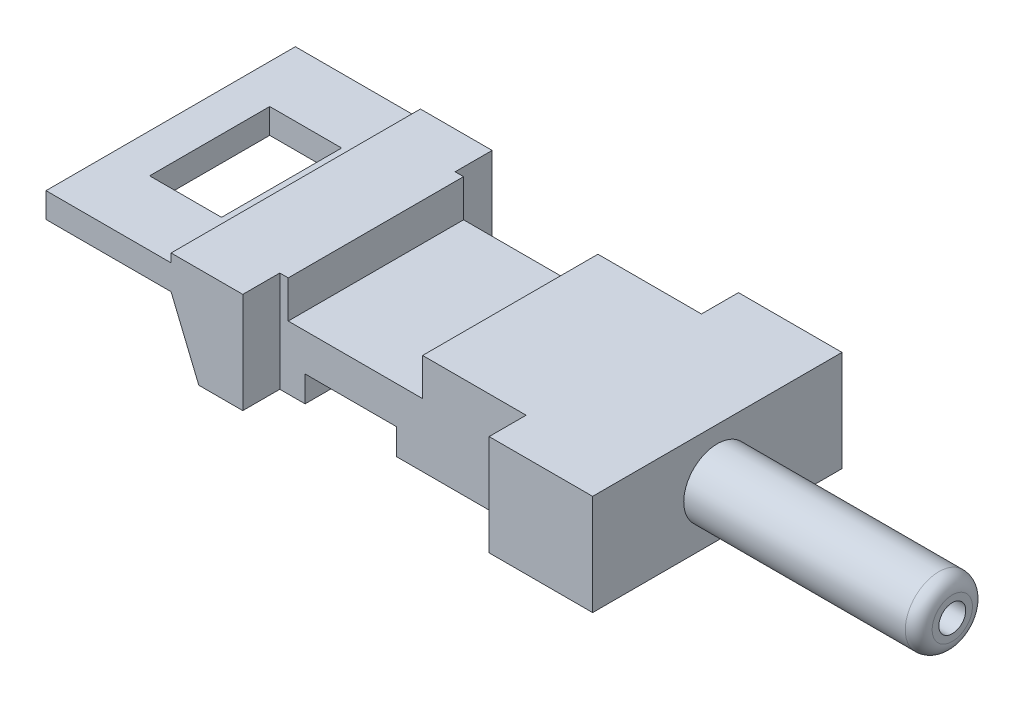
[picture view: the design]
ISO-10303-21;
HEADER;
FILE_DESCRIPTION(('STEP AP214'),'2;1');
FILE_NAME('part.step','',(''),(''),'','','');
FILE_SCHEMA(('AUTOMOTIVE_DESIGN { 1 0 10303 214 1 1 1 1 }'));
ENDSEC;
DATA;
#1=APPLICATION_CONTEXT('core data for automotive mechanical design processes');
#2=APPLICATION_PROTOCOL_DEFINITION('international standard','automotive_design',2000,#1);
#3=PRODUCT_CONTEXT('',#1,'mechanical');
#4=PRODUCT('Part','Part','',(#3));
#5=PRODUCT_RELATED_PRODUCT_CATEGORY('part','',(#4));
#6=PRODUCT_DEFINITION_FORMATION('','',#4);
#7=PRODUCT_DEFINITION_CONTEXT('part definition',#1,'design');
#8=PRODUCT_DEFINITION('design','',#6,#7);
#9=PRODUCT_DEFINITION_SHAPE('','',#8);
#10=(LENGTH_UNIT() NAMED_UNIT(*) SI_UNIT(.MILLI.,.METRE.));
#11=(NAMED_UNIT(*) PLANE_ANGLE_UNIT() SI_UNIT($,.RADIAN.));
#12=(NAMED_UNIT(*) SI_UNIT($,.STERADIAN.) SOLID_ANGLE_UNIT());
#13=UNCERTAINTY_MEASURE_WITH_UNIT(LENGTH_MEASURE(1.E-05),#10,'distance_accuracy_value','');
#14=(GEOMETRIC_REPRESENTATION_CONTEXT(3) GLOBAL_UNCERTAINTY_ASSIGNED_CONTEXT((#13)) GLOBAL_UNIT_ASSIGNED_CONTEXT((#10,
#11,#12)) REPRESENTATION_CONTEXT('',''));
#15=CARTESIAN_POINT('',(0.,0.,0.));
#16=DIRECTION('',(0.,0.,1.));
#17=DIRECTION('',(1.,0.,0.));
#18=AXIS2_PLACEMENT_3D('',#15,#16,#17);
#19=CARTESIAN_POINT('',(-40.7086650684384,5.,18.5695273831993));
#20=DIRECTION('',(0.,0.,-1.));
#21=DIRECTION('',(-1.,0.,0.));
#22=AXIS2_PLACEMENT_3D('',#19,#20,#21);
#23=PLANE('',#22);
#24=DIRECTION('',(1.,0.,0.));
#25=VECTOR('',#24,1.);
#26=CARTESIAN_POINT('',(-40.7086650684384,3.7238100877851,18.5695273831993));
#27=LINE('',#26,#25);
#28=CARTESIAN_POINT('',(-40.7086650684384,3.7238100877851,18.5695273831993));
#29=VERTEX_POINT('',#28);
#30=CARTESIAN_POINT('',(-22.0774506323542,3.7238100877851,18.5695273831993));
#31=VERTEX_POINT('',#30);
#32=EDGE_CURVE('E245',#29,#31,#27,.T.);
#33=ORIENTED_EDGE('',*,*,#32,.F.);
#34=DIRECTION('',(0.,-1.,0.));
#35=VECTOR('',#34,1.);
#36=CARTESIAN_POINT('',(-40.7086650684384,5.,18.5695273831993));
#37=LINE('',#36,#35);
#38=CARTESIAN_POINT('',(-40.7086650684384,0.,18.5695273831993));
#39=VERTEX_POINT('',#38);
#40=EDGE_CURVE('E255',#29,#39,#37,.T.);
#41=ORIENTED_EDGE('',*,*,#40,.T.);
#42=DIRECTION('',(-1.,0.,0.));
#43=VECTOR('',#42,1.);
#44=CARTESIAN_POINT('',(-40.7086650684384,0.,18.5695273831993));
#45=LINE('',#44,#43);
#46=CARTESIAN_POINT('',(-22.0774506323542,0.,18.5695273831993));
#47=VERTEX_POINT('',#46);
#48=EDGE_CURVE('E464',#47,#39,#45,.T.);
#49=ORIENTED_EDGE('',*,*,#48,.F.);
#50=DIRECTION('',(-0.381591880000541,0.924330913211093,0.));
#51=VECTOR('',#50,1.);
#52=CARTESIAN_POINT('',(-22.0774506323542,0.,18.5695273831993));
#53=LINE('',#52,#51);
#54=CARTESIAN_POINT('',(-17.9491468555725,-10.,18.5695273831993));
#55=VERTEX_POINT('',#54);
#56=EDGE_CURVE('E456',#55,#47,#53,.T.);
#57=ORIENTED_EDGE('',*,*,#56,.F.);
#58=DIRECTION('',(1.,0.,0.));
#59=VECTOR('',#58,1.);
#60=CARTESIAN_POINT('',(-40.7086650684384,-10.,18.5695273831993));
#61=LINE('',#60,#59);
#62=CARTESIAN_POINT('',(-11.3977082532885,-10.,18.5695273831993));
#63=VERTEX_POINT('',#62);
#64=EDGE_CURVE('E478',#55,#63,#61,.T.);
#65=ORIENTED_EDGE('',*,*,#64,.T.);
#66=DIRECTION('',(0.,1.,0.));
#67=VECTOR('',#66,1.);
#68=CARTESIAN_POINT('',(-11.3977082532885,-10.001,18.5695273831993));
#69=LINE('',#68,#67);
#70=CARTESIAN_POINT('',(-11.3977082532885,5.,18.5695273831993));
#71=VERTEX_POINT('',#70);
#72=EDGE_CURVE('E400',#63,#71,#69,.T.);
#73=ORIENTED_EDGE('',*,*,#72,.T.);
#74=DIRECTION('',(1.,0.,0.));
#75=VECTOR('',#74,1.);
#76=CARTESIAN_POINT('',(-40.7086650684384,5.,18.5695273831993));
#77=LINE('',#76,#75);
#78=CARTESIAN_POINT('',(-22.0774506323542,5.,18.5695273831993));
#79=VERTEX_POINT('',#78);
#80=EDGE_CURVE('E489',#79,#71,#77,.T.);
#81=ORIENTED_EDGE('',*,*,#80,.F.);
#82=DIRECTION('',(0.,1.,0.));
#83=VECTOR('',#82,1.);
#84=CARTESIAN_POINT('',(-22.0774506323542,3.7238100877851,18.5695273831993));
#85=LINE('',#84,#83);
#86=EDGE_CURVE('E46',#31,#79,#85,.T.);
#87=ORIENTED_EDGE('',*,*,#86,.F.);
#88=EDGE_LOOP('',(#33,#41,#49,#57,#65,#73,#81,#87));
#89=FACE_BOUND('',#88,.T.);
#90=ADVANCED_FACE('F31',(#89),#23,.F.);
#91=CARTESIAN_POINT('',(-40.7086650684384,5.,-18.5695273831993));
#92=DIRECTION('',(1.,0.,0.));
#93=DIRECTION('',(0.,0.,-1.));
#94=AXIS2_PLACEMENT_3D('',#91,#92,#93);
#95=PLANE('',#94);
#96=DIRECTION('',(0.,0.,-1.));
#97=VECTOR('',#96,1.);
#98=CARTESIAN_POINT('',(-40.7086650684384,3.7238100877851,18.5695273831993));
#99=LINE('',#98,#97);
#100=CARTESIAN_POINT('',(-40.7086650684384,3.7238100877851,-18.5695273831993));
#101=VERTEX_POINT('',#100);
#102=EDGE_CURVE('E241',#29,#101,#99,.T.);
#103=ORIENTED_EDGE('',*,*,#102,.T.);
#104=DIRECTION('',(0.,-1.,0.));
#105=VECTOR('',#104,1.);
#106=CARTESIAN_POINT('',(-40.7086650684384,5.,-18.5695273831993));
#107=LINE('',#106,#105);
#108=CARTESIAN_POINT('',(-40.7086650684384,0.,-18.5695273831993));
#109=VERTEX_POINT('',#108);
#110=EDGE_CURVE('E497',#101,#109,#107,.T.);
#111=ORIENTED_EDGE('',*,*,#110,.T.);
#112=DIRECTION('',(0.,0.,1.));
#113=VECTOR('',#112,1.);
#114=CARTESIAN_POINT('',(-40.7086650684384,0.,-18.5695273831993));
#115=LINE('',#114,#113);
#116=EDGE_CURVE('E262',#109,#39,#115,.T.);
#117=ORIENTED_EDGE('',*,*,#116,.T.);
#118=ORIENTED_EDGE('',*,*,#40,.F.);
#119=EDGE_LOOP('',(#103,#111,#117,#118));
#120=FACE_BOUND('',#119,.T.);
#121=ADVANCED_FACE('F33',(#120),#95,.F.);
#122=CARTESIAN_POINT('',(-40.7086650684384,5.,-18.5695273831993));
#123=DIRECTION('',(0.,0.,1.));
#124=DIRECTION('',(1.,0.,0.));
#125=AXIS2_PLACEMENT_3D('',#122,#123,#124);
#126=PLANE('',#125);
#127=DIRECTION('',(-1.,0.,0.));
#128=VECTOR('',#127,1.);
#129=CARTESIAN_POINT('',(-40.7086650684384,3.7238100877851,-18.5695273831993));
#130=LINE('',#129,#128);
#131=CARTESIAN_POINT('',(-22.0774506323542,3.7238100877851,-18.5695273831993));
#132=VERTEX_POINT('',#131);
#133=EDGE_CURVE('E247',#132,#101,#130,.T.);
#134=ORIENTED_EDGE('',*,*,#133,.F.);
#135=DIRECTION('',(0.,-1.,0.));
#136=VECTOR('',#135,1.);
#137=CARTESIAN_POINT('',(-22.0774506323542,5.00000000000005,-18.5695273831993));
#138=LINE('',#137,#136);
#139=CARTESIAN_POINT('',(-22.0774506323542,5.,-18.5695273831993));
#140=VERTEX_POINT('',#139);
#141=EDGE_CURVE('E299',#140,#132,#138,.T.);
#142=ORIENTED_EDGE('',*,*,#141,.F.);
#143=DIRECTION('',(-1.,0.,0.));
#144=VECTOR('',#143,1.);
#145=CARTESIAN_POINT('',(-40.7086650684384,5.,-18.5695273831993));
#146=LINE('',#145,#144);
#147=CARTESIAN_POINT('',(-11.3977082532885,5.,-18.5695273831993));
#148=VERTEX_POINT('',#147);
#149=EDGE_CURVE('E493',#148,#140,#146,.T.);
#150=ORIENTED_EDGE('',*,*,#149,.F.);
#151=DIRECTION('',(0.,1.,0.));
#152=VECTOR('',#151,1.);
#153=CARTESIAN_POINT('',(-11.3977082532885,-10.001,-18.5695273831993));
#154=LINE('',#153,#152);
#155=CARTESIAN_POINT('',(-11.3977082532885,-10.,-18.5695273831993));
#156=VERTEX_POINT('',#155);
#157=EDGE_CURVE('E356',#156,#148,#154,.T.);
#158=ORIENTED_EDGE('',*,*,#157,.F.);
#159=DIRECTION('',(-1.,0.,0.));
#160=VECTOR('',#159,1.);
#161=CARTESIAN_POINT('',(-40.7086650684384,-10.,-18.5695273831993));
#162=LINE('',#161,#160);
#163=CARTESIAN_POINT('',(-17.9491468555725,-10.,-18.5695273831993));
#164=VERTEX_POINT('',#163);
#165=EDGE_CURVE('E484',#156,#164,#162,.T.);
#166=ORIENTED_EDGE('',*,*,#165,.T.);
#167=DIRECTION('',(-0.381591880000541,0.924330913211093,0.));
#168=VECTOR('',#167,1.);
#169=CARTESIAN_POINT('',(-22.0774506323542,0.,-18.5695273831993));
#170=LINE('',#169,#168);
#171=CARTESIAN_POINT('',(-22.0774506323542,0.,-18.5695273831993));
#172=VERTEX_POINT('',#171);
#173=EDGE_CURVE('E466',#164,#172,#170,.T.);
#174=ORIENTED_EDGE('',*,*,#173,.T.);
#175=DIRECTION('',(-1.,0.,0.));
#176=VECTOR('',#175,1.);
#177=CARTESIAN_POINT('',(-40.7086650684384,0.,-18.5695273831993));
#178=LINE('',#177,#176);
#179=EDGE_CURVE('E469',#172,#109,#178,.T.);
#180=ORIENTED_EDGE('',*,*,#179,.T.);
#181=ORIENTED_EDGE('',*,*,#110,.F.);
#182=EDGE_LOOP('',(#134,#142,#150,#158,#166,#174,#180,#181));
#183=FACE_BOUND('',#182,.T.);
#184=ADVANCED_FACE('F603',(#183),#126,.F.);
#185=CARTESIAN_POINT('',(-40.7086650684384,5.,18.5695273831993));
#186=DIRECTION('',(0.,1.,0.));
#187=DIRECTION('',(0.,0.,1.));
#188=AXIS2_PLACEMENT_3D('',#185,#186,#187);
#189=PLANE('',#188);
#190=ORIENTED_EDGE('',*,*,#149,.T.);
#191=DIRECTION('',(0.,0.,-1.));
#192=VECTOR('',#191,1.);
#193=CARTESIAN_POINT('',(-22.0774506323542,5.,18.5695273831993));
#194=LINE('',#193,#192);
#195=EDGE_CURVE('E251',#79,#140,#194,.T.);
#196=ORIENTED_EDGE('',*,*,#195,.F.);
#197=ORIENTED_EDGE('',*,*,#80,.T.);
#198=DIRECTION('',(0.,0.,1.));
#199=VECTOR('',#198,1.);
#200=CARTESIAN_POINT('',(-11.3977082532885,5.,13.058004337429));
#201=LINE('',#200,#199);
#202=CARTESIAN_POINT('',(-11.3977082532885,5.,13.058004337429));
#203=VERTEX_POINT('',#202);
#204=EDGE_CURVE('E396',#203,#71,#201,.T.);
#205=ORIENTED_EDGE('',*,*,#204,.F.);
#206=DIRECTION('',(-1.,0.,0.));
#207=VECTOR('',#206,1.);
#208=CARTESIAN_POINT('',(25.2903479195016,5.,13.058004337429));
#209=LINE('',#208,#207);
#210=CARTESIAN_POINT('',(-10.1412679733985,5.,13.058004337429));
#211=VERTEX_POINT('',#210);
#212=EDGE_CURVE('E392',#211,#203,#209,.T.);
#213=ORIENTED_EDGE('',*,*,#212,.F.);
#214=DIRECTION('',(0.,0.,1.));
#215=VECTOR('',#214,1.);
#216=CARTESIAN_POINT('',(-10.1412679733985,5.,-18.5695273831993));
#217=LINE('',#216,#215);
#218=CARTESIAN_POINT('',(-10.1412679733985,5.,-13.058004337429));
#219=VERTEX_POINT('',#218);
#220=EDGE_CURVE('E448',#219,#211,#217,.T.);
#221=ORIENTED_EDGE('',*,*,#220,.F.);
#222=DIRECTION('',(1.,0.,0.));
#223=VECTOR('',#222,1.);
#224=CARTESIAN_POINT('',(25.2903479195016,5.,-13.0580043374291));
#225=LINE('',#224,#223);
#226=CARTESIAN_POINT('',(-11.3977082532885,5.,-13.058004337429));
#227=VERTEX_POINT('',#226);
#228=EDGE_CURVE('E352',#227,#219,#225,.T.);
#229=ORIENTED_EDGE('',*,*,#228,.F.);
#230=DIRECTION('',(0.,0.,1.));
#231=VECTOR('',#230,1.);
#232=CARTESIAN_POINT('',(-11.3977082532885,5.,-13.058004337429));
#233=LINE('',#232,#231);
#234=EDGE_CURVE('E348',#148,#227,#233,.T.);
#235=ORIENTED_EDGE('',*,*,#234,.F.);
#236=EDGE_LOOP('',(#190,#196,#197,#205,#213,#221,#229,#235));
#237=FACE_BOUND('',#236,.T.);
#238=ADVANCED_FACE('F570',(#237),#189,.T.);
#239=CARTESIAN_POINT('',(-34.9005323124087,-10.001,-8.94289846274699));
#240=DIRECTION('',(-1.,0.,0.));
#241=DIRECTION('',(0.,0.,1.));
#242=AXIS2_PLACEMENT_3D('',#239,#240,#241);
#243=PLANE('',#242);
#244=DIRECTION('',(0.,0.,-1.));
#245=VECTOR('',#244,1.);
#246=CARTESIAN_POINT('',(-34.9005323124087,3.7238100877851,-8.94289846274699));
#247=LINE('',#246,#245);
#248=CARTESIAN_POINT('',(-34.9005323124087,3.7238100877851,8.94289846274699));
#249=VERTEX_POINT('',#248);
#250=CARTESIAN_POINT('',(-34.9005323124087,3.7238100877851,-8.94289846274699));
#251=VERTEX_POINT('',#250);
#252=EDGE_CURVE('E925',#249,#251,#247,.T.);
#253=ORIENTED_EDGE('',*,*,#252,.F.);
#254=DIRECTION('',(0.,1.,0.));
#255=VECTOR('',#254,1.);
#256=CARTESIAN_POINT('',(-34.9005323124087,-10.001,8.94289846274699));
#257=LINE('',#256,#255);
#258=CARTESIAN_POINT('',(-34.9005323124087,0.,8.94289846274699));
#259=VERTEX_POINT('',#258);
#260=EDGE_CURVE('E433',#259,#249,#257,.T.);
#261=ORIENTED_EDGE('',*,*,#260,.F.);
#262=DIRECTION('',(0.,0.,-1.));
#263=VECTOR('',#262,1.);
#264=CARTESIAN_POINT('',(-34.9005323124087,0.,-8.94289846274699));
#265=LINE('',#264,#263);
#266=CARTESIAN_POINT('',(-34.9005323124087,0.,-8.94289846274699));
#267=VERTEX_POINT('',#266);
#268=EDGE_CURVE('E430',#259,#267,#265,.T.);
#269=ORIENTED_EDGE('',*,*,#268,.T.);
#270=DIRECTION('',(0.,1.,0.));
#271=VECTOR('',#270,1.);
#272=CARTESIAN_POINT('',(-34.9005323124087,-10.001,-8.94289846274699));
#273=LINE('',#272,#271);
#274=EDGE_CURVE('E434',#267,#251,#273,.T.);
#275=ORIENTED_EDGE('',*,*,#274,.T.);
#276=EDGE_LOOP('',(#253,#261,#269,#275));
#277=FACE_BOUND('',#276,.T.);
#278=ADVANCED_FACE('F618',(#277),#243,.F.);
#279=CARTESIAN_POINT('',(-34.9005323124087,-10.001,-8.94289846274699));
#280=DIRECTION('',(0.,0.,-1.));
#281=DIRECTION('',(-1.,0.,0.));
#282=AXIS2_PLACEMENT_3D('',#279,#280,#281);
#283=PLANE('',#282);
#284=DIRECTION('',(1.,0.,0.));
#285=VECTOR('',#284,1.);
#286=CARTESIAN_POINT('',(-34.9005323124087,3.7238100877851,-8.94289846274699));
#287=LINE('',#286,#285);
#288=CARTESIAN_POINT('',(-24.1925625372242,3.7238100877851,-8.94289846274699));
#289=VERTEX_POINT('',#288);
#290=EDGE_CURVE('E54',#251,#289,#287,.T.);
#291=ORIENTED_EDGE('',*,*,#290,.F.);
#292=ORIENTED_EDGE('',*,*,#274,.F.);
#293=DIRECTION('',(1.,0.,0.));
#294=VECTOR('',#293,1.);
#295=CARTESIAN_POINT('',(-34.9005323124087,0.,-8.94289846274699));
#296=LINE('',#295,#294);
#297=CARTESIAN_POINT('',(-24.1925625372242,0.,-8.94289846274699));
#298=VERTEX_POINT('',#297);
#299=EDGE_CURVE('E427',#267,#298,#296,.T.);
#300=ORIENTED_EDGE('',*,*,#299,.T.);
#301=DIRECTION('',(0.,1.,0.));
#302=VECTOR('',#301,1.);
#303=CARTESIAN_POINT('',(-24.1925625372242,-10.001,-8.94289846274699));
#304=LINE('',#303,#302);
#305=EDGE_CURVE('E437',#298,#289,#304,.T.);
#306=ORIENTED_EDGE('',*,*,#305,.T.);
#307=EDGE_LOOP('',(#291,#292,#300,#306));
#308=FACE_BOUND('',#307,.T.);
#309=ADVANCED_FACE('F623',(#308),#283,.F.);
#310=CARTESIAN_POINT('',(-24.1925625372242,-10.001,-8.94289846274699));
#311=DIRECTION('',(1.,0.,0.));
#312=DIRECTION('',(0.,0.,-1.));
#313=AXIS2_PLACEMENT_3D('',#310,#311,#312);
#314=PLANE('',#313);
#315=DIRECTION('',(0.,0.,1.));
#316=VECTOR('',#315,1.);
#317=CARTESIAN_POINT('',(-24.1925625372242,3.7238100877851,-8.94289846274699));
#318=LINE('',#317,#316);
#319=CARTESIAN_POINT('',(-24.1925625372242,3.7238100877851,8.94289846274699));
#320=VERTEX_POINT('',#319);
#321=EDGE_CURVE('E258',#289,#320,#318,.T.);
#322=ORIENTED_EDGE('',*,*,#321,.F.);
#323=ORIENTED_EDGE('',*,*,#305,.F.);
#324=DIRECTION('',(0.,0.,1.));
#325=VECTOR('',#324,1.);
#326=CARTESIAN_POINT('',(-24.1925625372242,0.,-8.94289846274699));
#327=LINE('',#326,#325);
#328=CARTESIAN_POINT('',(-24.1925625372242,0.,8.94289846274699));
#329=VERTEX_POINT('',#328);
#330=EDGE_CURVE('E425',#298,#329,#327,.T.);
#331=ORIENTED_EDGE('',*,*,#330,.T.);
#332=DIRECTION('',(0.,1.,0.));
#333=VECTOR('',#332,1.);
#334=CARTESIAN_POINT('',(-24.1925625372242,-10.001,8.94289846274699));
#335=LINE('',#334,#333);
#336=EDGE_CURVE('E439',#329,#320,#335,.T.);
#337=ORIENTED_EDGE('',*,*,#336,.T.);
#338=EDGE_LOOP('',(#322,#323,#331,#337));
#339=FACE_BOUND('',#338,.T.);
#340=ADVANCED_FACE('F637',(#339),#314,.F.);
#341=CARTESIAN_POINT('',(-34.9005323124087,-10.001,8.94289846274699));
#342=DIRECTION('',(0.,0.,1.));
#343=DIRECTION('',(1.,0.,0.));
#344=AXIS2_PLACEMENT_3D('',#341,#342,#343);
#345=PLANE('',#344);
#346=DIRECTION('',(-1.,0.,0.));
#347=VECTOR('',#346,1.);
#348=CARTESIAN_POINT('',(-34.9005323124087,3.7238100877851,8.94289846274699));
#349=LINE('',#348,#347);
#350=EDGE_CURVE('E11',#320,#249,#349,.T.);
#351=ORIENTED_EDGE('',*,*,#350,.F.);
#352=ORIENTED_EDGE('',*,*,#336,.F.);
#353=DIRECTION('',(-1.,0.,0.));
#354=VECTOR('',#353,1.);
#355=CARTESIAN_POINT('',(-34.9005323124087,0.,8.94289846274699));
#356=LINE('',#355,#354);
#357=EDGE_CURVE('E436',#329,#259,#356,.T.);
#358=ORIENTED_EDGE('',*,*,#357,.T.);
#359=ORIENTED_EDGE('',*,*,#260,.T.);
#360=EDGE_LOOP('',(#351,#352,#358,#359));
#361=FACE_BOUND('',#360,.T.);
#362=ADVANCED_FACE('F633',(#361),#345,.F.);
#363=CARTESIAN_POINT('',(40.7086650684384,5.,-18.5695273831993));
#364=DIRECTION('',(-1.,0.,0.));
#365=DIRECTION('',(0.,0.,1.));
#366=AXIS2_PLACEMENT_3D('',#363,#364,#365);
#367=PLANE('',#366);
#368=DIRECTION('',(0.,-1.,0.));
#369=VECTOR('',#368,1.);
#370=CARTESIAN_POINT('',(40.7086650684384,5.,18.5695273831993));
#371=LINE('',#370,#369);
#372=CARTESIAN_POINT('',(40.7086650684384,5.,18.5695273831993));
#373=VERTEX_POINT('',#372);
#374=CARTESIAN_POINT('',(40.7086650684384,-10.,18.5695273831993));
#375=VERTEX_POINT('',#374);
#376=EDGE_CURVE('E264',#373,#375,#371,.T.);
#377=ORIENTED_EDGE('',*,*,#376,.T.);
#378=DIRECTION('',(0.,0.,-1.));
#379=VECTOR('',#378,1.);
#380=CARTESIAN_POINT('',(40.7086650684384,-10.,-18.5695273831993));
#381=LINE('',#380,#379);
#382=CARTESIAN_POINT('',(40.7086650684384,-10.,-18.5695273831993));
#383=VERTEX_POINT('',#382);
#384=EDGE_CURVE('E481',#375,#383,#381,.T.);
#385=ORIENTED_EDGE('',*,*,#384,.T.);
#386=DIRECTION('',(0.,-1.,0.));
#387=VECTOR('',#386,1.);
#388=CARTESIAN_POINT('',(40.7086650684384,5.,-18.5695273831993));
#389=LINE('',#388,#387);
#390=CARTESIAN_POINT('',(40.7086650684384,5.,-18.5695273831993));
#391=VERTEX_POINT('',#390);
#392=EDGE_CURVE('E270',#391,#383,#389,.T.);
#393=ORIENTED_EDGE('',*,*,#392,.F.);
#394=DIRECTION('',(0.,0.,-1.));
#395=VECTOR('',#394,1.);
#396=CARTESIAN_POINT('',(40.7086650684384,5.,-18.5695273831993));
#397=LINE('',#396,#395);
#398=EDGE_CURVE('E491',#373,#391,#397,.T.);
#399=ORIENTED_EDGE('',*,*,#398,.F.);
#400=EDGE_LOOP('',(#377,#385,#393,#399));
#401=FACE_BOUND('',#400,.T.);
#402=CARTESIAN_POINT('',(40.7086650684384,-2.5,0.));
#403=DIRECTION('',(-1.,0.,0.));
#404=DIRECTION('',(0.,0.,1.));
#405=AXIS2_PLACEMENT_3D('',#402,#403,#404);
#406=CIRCLE('',#405,5.);
#407=CARTESIAN_POINT('',(40.7086650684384,-2.5,5.00000000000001));
#408=VERTEX_POINT('',#407);
#409=EDGE_CURVE('E263',#408,#408,#406,.F.);
#410=ORIENTED_EDGE('',*,*,#409,.F.);
#411=EDGE_LOOP('',(#410));
#412=FACE_BOUND('',#411,.T.);
#413=ADVANCED_FACE('F506',(#401,#412),#367,.F.);
#414=CARTESIAN_POINT('',(25.2903479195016,-10.,-18.5695273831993));
#415=VERTEX_POINT('',#414);
#416=EDGE_CURVE('E485',#383,#415,#162,.T.);
#417=ORIENTED_EDGE('',*,*,#416,.T.);
#418=DIRECTION('',(0.,1.,0.));
#419=VECTOR('',#418,1.);
#420=CARTESIAN_POINT('',(25.2903479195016,-10.001,-18.5695273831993));
#421=LINE('',#420,#419);
#422=CARTESIAN_POINT('',(25.2903479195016,5.,-18.5695273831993));
#423=VERTEX_POINT('',#422);
#424=EDGE_CURVE('E357',#415,#423,#421,.T.);
#425=ORIENTED_EDGE('',*,*,#424,.T.);
#426=EDGE_CURVE('E494',#391,#423,#146,.T.);
#427=ORIENTED_EDGE('',*,*,#426,.F.);
#428=ORIENTED_EDGE('',*,*,#392,.T.);
#429=EDGE_LOOP('',(#417,#425,#427,#428));
#430=FACE_BOUND('',#429,.T.);
#431=ADVANCED_FACE('F501',(#430),#126,.F.);
#432=CARTESIAN_POINT('',(-40.7086650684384,-10.,18.5695273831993));
#433=DIRECTION('',(0.,1.,0.));
#434=DIRECTION('',(0.,0.,1.));
#435=AXIS2_PLACEMENT_3D('',#432,#433,#434);
#436=PLANE('',#435);
#437=DIRECTION('',(0.,0.,-1.));
#438=VECTOR('',#437,1.);
#439=CARTESIAN_POINT('',(-11.3977082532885,-10.,-13.058004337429));
#440=LINE('',#439,#438);
#441=CARTESIAN_POINT('',(-11.3977082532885,-10.,-13.058004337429));
#442=VERTEX_POINT('',#441);
#443=EDGE_CURVE('E360',#442,#156,#440,.T.);
#444=ORIENTED_EDGE('',*,*,#443,.F.);
#445=DIRECTION('',(-1.,0.,0.));
#446=VECTOR('',#445,1.);
#447=CARTESIAN_POINT('',(25.2903479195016,-10.,-13.0580043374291));
#448=LINE('',#447,#446);
#449=CARTESIAN_POINT('',(-7.62838741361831,-10.,-13.058004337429));
#450=VERTEX_POINT('',#449);
#451=EDGE_CURVE('E342',#450,#442,#448,.T.);
#452=ORIENTED_EDGE('',*,*,#451,.F.);
#453=DIRECTION('',(0.,0.,1.));
#454=VECTOR('',#453,1.);
#455=CARTESIAN_POINT('',(-7.62838741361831,-10.,-18.5695273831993));
#456=LINE('',#455,#454);
#457=CARTESIAN_POINT('',(-7.62838741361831,-10.,13.058004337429));
#458=VERTEX_POINT('',#457);
#459=EDGE_CURVE('E446',#450,#458,#456,.T.);
#460=ORIENTED_EDGE('',*,*,#459,.T.);
#461=DIRECTION('',(1.,0.,0.));
#462=VECTOR('',#461,1.);
#463=CARTESIAN_POINT('',(25.2903479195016,-10.,13.058004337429));
#464=LINE('',#463,#462);
#465=CARTESIAN_POINT('',(-11.3977082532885,-10.,13.058004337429));
#466=VERTEX_POINT('',#465);
#467=EDGE_CURVE('E419',#466,#458,#464,.T.);
#468=ORIENTED_EDGE('',*,*,#467,.F.);
#469=DIRECTION('',(0.,0.,-1.));
#470=VECTOR('',#469,1.);
#471=CARTESIAN_POINT('',(-11.3977082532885,-10.,13.058004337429));
#472=LINE('',#471,#470);
#473=EDGE_CURVE('E386',#63,#466,#472,.T.);
#474=ORIENTED_EDGE('',*,*,#473,.F.);
#475=ORIENTED_EDGE('',*,*,#64,.F.);
#476=DIRECTION('',(0.,0.,1.));
#477=VECTOR('',#476,1.);
#478=CARTESIAN_POINT('',(-17.9491468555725,-10.,-18.5695273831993));
#479=LINE('',#478,#477);
#480=EDGE_CURVE('E472',#164,#55,#479,.T.);
#481=ORIENTED_EDGE('',*,*,#480,.F.);
#482=ORIENTED_EDGE('',*,*,#165,.F.);
#483=EDGE_LOOP('',(#444,#452,#460,#468,#474,#475,#481,#482));
#484=FACE_BOUND('',#483,.T.);
#485=ADVANCED_FACE('F556',(#484),#436,.F.);
#486=DIRECTION('',(0.,0.,-1.));
#487=VECTOR('',#486,1.);
#488=CARTESIAN_POINT('',(25.2903479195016,5.,-18.5695273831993));
#489=LINE('',#488,#487);
#490=CARTESIAN_POINT('',(25.2903479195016,5.,-13.0580043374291));
#491=VERTEX_POINT('',#490);
#492=EDGE_CURVE('E354',#491,#423,#489,.T.);
#493=ORIENTED_EDGE('',*,*,#492,.F.);
#494=CARTESIAN_POINT('',(9.87203077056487,5.,-13.0580043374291));
#495=VERTEX_POINT('',#494);
#496=EDGE_CURVE('E351',#495,#491,#225,.T.);
#497=ORIENTED_EDGE('',*,*,#496,.F.);
#498=DIRECTION('',(0.,0.,1.));
#499=VECTOR('',#498,1.);
#500=CARTESIAN_POINT('',(9.87203077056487,5.,-18.5695273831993));
#501=LINE('',#500,#499);
#502=CARTESIAN_POINT('',(9.87203077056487,5.,13.058004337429));
#503=VERTEX_POINT('',#502);
#504=EDGE_CURVE('E454',#495,#503,#501,.T.);
#505=ORIENTED_EDGE('',*,*,#504,.T.);
#506=CARTESIAN_POINT('',(25.2903479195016,5.,13.058004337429));
#507=VERTEX_POINT('',#506);
#508=EDGE_CURVE('E393',#507,#503,#209,.T.);
#509=ORIENTED_EDGE('',*,*,#508,.F.);
#510=DIRECTION('',(0.,0.,-1.));
#511=VECTOR('',#510,1.);
#512=CARTESIAN_POINT('',(25.2903479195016,5.,18.5695273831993));
#513=LINE('',#512,#511);
#514=CARTESIAN_POINT('',(25.2903479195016,5.,18.5695273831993));
#515=VERTEX_POINT('',#514);
#516=EDGE_CURVE('E389',#515,#507,#513,.T.);
#517=ORIENTED_EDGE('',*,*,#516,.F.);
#518=EDGE_CURVE('E488',#515,#373,#77,.T.);
#519=ORIENTED_EDGE('',*,*,#518,.T.);
#520=ORIENTED_EDGE('',*,*,#398,.T.);
#521=ORIENTED_EDGE('',*,*,#426,.T.);
#522=EDGE_LOOP('',(#493,#497,#505,#509,#517,#519,#520,#521));
#523=FACE_BOUND('',#522,.T.);
#524=ADVANCED_FACE('F520',(#523),#189,.T.);
#525=ORIENTED_EDGE('',*,*,#518,.F.);
#526=DIRECTION('',(0.,1.,0.));
#527=VECTOR('',#526,1.);
#528=CARTESIAN_POINT('',(25.2903479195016,-10.001,18.5695273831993));
#529=LINE('',#528,#527);
#530=CARTESIAN_POINT('',(25.2903479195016,-10.,18.5695273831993));
#531=VERTEX_POINT('',#530);
#532=EDGE_CURVE('E399',#531,#515,#529,.T.);
#533=ORIENTED_EDGE('',*,*,#532,.F.);
#534=EDGE_CURVE('E474',#531,#375,#61,.T.);
#535=ORIENTED_EDGE('',*,*,#534,.T.);
#536=ORIENTED_EDGE('',*,*,#376,.F.);
#537=EDGE_LOOP('',(#525,#533,#535,#536));
#538=FACE_BOUND('',#537,.T.);
#539=ADVANCED_FACE('F527',(#538),#23,.F.);
#540=DIRECTION('',(-1.,0.,0.));
#541=VECTOR('',#540,1.);
#542=CARTESIAN_POINT('',(37.7086650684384,-10.,5.00000000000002));
#543=LINE('',#542,#541);
#544=CARTESIAN_POINT('',(37.7086650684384,-10.,5.00000000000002));
#545=VERTEX_POINT('',#544);
#546=CARTESIAN_POINT('',(28.7663146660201,-10.,5.00000000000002));
#547=VERTEX_POINT('',#546);
#548=EDGE_CURVE('E308',#545,#547,#543,.T.);
#549=ORIENTED_EDGE('',*,*,#548,.F.);
#550=DIRECTION('',(0.,0.,1.));
#551=VECTOR('',#550,1.);
#552=CARTESIAN_POINT('',(37.7086650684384,-10.,5.00000000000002));
#553=LINE('',#552,#551);
#554=CARTESIAN_POINT('',(37.7086650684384,-10.,-4.99999999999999));
#555=VERTEX_POINT('',#554);
#556=EDGE_CURVE('E302',#555,#545,#553,.T.);
#557=ORIENTED_EDGE('',*,*,#556,.F.);
#558=DIRECTION('',(1.,0.,0.));
#559=VECTOR('',#558,1.);
#560=CARTESIAN_POINT('',(37.7086650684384,-10.,-4.99999999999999));
#561=LINE('',#560,#559);
#562=CARTESIAN_POINT('',(28.7663146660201,-10.,-4.99999999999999));
#563=VERTEX_POINT('',#562);
#564=EDGE_CURVE('E314',#563,#555,#561,.T.);
#565=ORIENTED_EDGE('',*,*,#564,.F.);
#566=DIRECTION('',(0.,0.,-1.));
#567=VECTOR('',#566,1.);
#568=CARTESIAN_POINT('',(28.7663146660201,-10.,5.00000000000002));
#569=LINE('',#568,#567);
#570=EDGE_CURVE('E311',#547,#563,#569,.T.);
#571=ORIENTED_EDGE('',*,*,#570,.F.);
#572=EDGE_LOOP('',(#549,#557,#565,#571));
#573=FACE_BOUND('',#572,.T.);
#574=DIRECTION('',(-1.,0.,0.));
#575=VECTOR('',#574,1.);
#576=CARTESIAN_POINT('',(25.2903479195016,-10.,-13.0580043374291));
#577=LINE('',#576,#575);
#578=CARTESIAN_POINT('',(25.2903479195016,-10.,-13.0580043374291));
#579=VERTEX_POINT('',#578);
#580=CARTESIAN_POINT('',(6.01296419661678,-10.,-13.058004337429));
#581=VERTEX_POINT('',#580);
#582=EDGE_CURVE('E373',#579,#581,#577,.T.);
#583=ORIENTED_EDGE('',*,*,#582,.F.);
#584=DIRECTION('',(0.,0.,1.));
#585=VECTOR('',#584,1.);
#586=CARTESIAN_POINT('',(25.2903479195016,-10.,-18.5695273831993));
#587=LINE('',#586,#585);
#588=EDGE_CURVE('E345',#415,#579,#587,.T.);
#589=ORIENTED_EDGE('',*,*,#588,.F.);
#590=ORIENTED_EDGE('',*,*,#416,.F.);
#591=ORIENTED_EDGE('',*,*,#384,.F.);
#592=ORIENTED_EDGE('',*,*,#534,.F.);
#593=DIRECTION('',(0.,0.,1.));
#594=VECTOR('',#593,1.);
#595=CARTESIAN_POINT('',(25.2903479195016,-10.,18.5695273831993));
#596=LINE('',#595,#594);
#597=CARTESIAN_POINT('',(25.2903479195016,-10.,13.058004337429));
#598=VERTEX_POINT('',#597);
#599=EDGE_CURVE('E403',#598,#531,#596,.T.);
#600=ORIENTED_EDGE('',*,*,#599,.F.);
#601=DIRECTION('',(1.,0.,0.));
#602=VECTOR('',#601,1.);
#603=CARTESIAN_POINT('',(25.2903479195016,-10.,13.058004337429));
#604=LINE('',#603,#602);
#605=CARTESIAN_POINT('',(6.01296419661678,-10.,13.058004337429));
#606=VERTEX_POINT('',#605);
#607=EDGE_CURVE('E383',#606,#598,#604,.T.);
#608=ORIENTED_EDGE('',*,*,#607,.F.);
#609=DIRECTION('',(0.,0.,1.));
#610=VECTOR('',#609,1.);
#611=CARTESIAN_POINT('',(6.01296419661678,-10.,-18.5695273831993));
#612=LINE('',#611,#610);
#613=EDGE_CURVE('E445',#581,#606,#612,.T.);
#614=ORIENTED_EDGE('',*,*,#613,.F.);
#615=EDGE_LOOP('',(#583,#589,#590,#591,#592,#600,#608,#614));
#616=FACE_BOUND('',#615,.T.);
#617=ADVANCED_FACE('F513',(#573,#616),#436,.F.);
#618=CARTESIAN_POINT('',(-40.7086650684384,0.,-18.5695273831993));
#619=DIRECTION('',(0.,1.,0.));
#620=DIRECTION('',(0.,0.,1.));
#621=AXIS2_PLACEMENT_3D('',#618,#619,#620);
#622=PLANE('',#621);
#623=ORIENTED_EDGE('',*,*,#299,.F.);
#624=ORIENTED_EDGE('',*,*,#268,.F.);
#625=ORIENTED_EDGE('',*,*,#357,.F.);
#626=ORIENTED_EDGE('',*,*,#330,.F.);
#627=EDGE_LOOP('',(#623,#624,#625,#626));
#628=FACE_BOUND('',#627,.T.);
#629=ORIENTED_EDGE('',*,*,#48,.T.);
#630=ORIENTED_EDGE('',*,*,#116,.F.);
#631=ORIENTED_EDGE('',*,*,#179,.F.);
#632=DIRECTION('',(0.,0.,1.));
#633=VECTOR('',#632,1.);
#634=CARTESIAN_POINT('',(-22.0774506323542,0.,-18.5695273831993));
#635=LINE('',#634,#633);
#636=EDGE_CURVE('E475',#172,#47,#635,.T.);
#637=ORIENTED_EDGE('',*,*,#636,.T.);
#638=EDGE_LOOP('',(#629,#630,#631,#637));
#639=FACE_BOUND('',#638,.T.);
#640=ADVANCED_FACE('F595',(#628,#639),#622,.F.);
#641=CARTESIAN_POINT('',(-22.0774506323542,0.,-18.5695273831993));
#642=DIRECTION('',(0.924330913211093,0.381591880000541,0.));
#643=DIRECTION('',(-0.381591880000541,0.924330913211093,0.));
#644=AXIS2_PLACEMENT_3D('',#641,#642,#643);
#645=PLANE('',#644);
#646=ORIENTED_EDGE('',*,*,#56,.T.);
#647=ORIENTED_EDGE('',*,*,#636,.F.);
#648=ORIENTED_EDGE('',*,*,#173,.F.);
#649=ORIENTED_EDGE('',*,*,#480,.T.);
#650=EDGE_LOOP('',(#646,#647,#648,#649));
#651=FACE_BOUND('',#650,.T.);
#652=ADVANCED_FACE('F588',(#651),#645,.F.);
#653=CARTESIAN_POINT('',(9.87203077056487,-0.570466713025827,-18.5695273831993));
#654=DIRECTION('',(1.,0.,0.));
#655=DIRECTION('',(0.,0.,-1.));
#656=AXIS2_PLACEMENT_3D('',#653,#654,#655);
#657=PLANE('',#656);
#658=ORIENTED_EDGE('',*,*,#504,.F.);
#659=DIRECTION('',(0.,1.,0.));
#660=VECTOR('',#659,1.);
#661=CARTESIAN_POINT('',(9.87203077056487,-10.001,-13.0580043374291));
#662=LINE('',#661,#660);
#663=CARTESIAN_POINT('',(9.87203077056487,-0.570466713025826,-13.0580043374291));
#664=VERTEX_POINT('',#663);
#665=EDGE_CURVE('E340',#664,#495,#662,.T.);
#666=ORIENTED_EDGE('',*,*,#665,.F.);
#667=DIRECTION('',(0.,0.,1.));
#668=VECTOR('',#667,1.);
#669=CARTESIAN_POINT('',(9.87203077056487,-0.570466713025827,-18.5695273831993));
#670=LINE('',#669,#668);
#671=CARTESIAN_POINT('',(9.87203077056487,-0.570466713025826,13.058004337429));
#672=VERTEX_POINT('',#671);
#673=EDGE_CURVE('E457',#664,#672,#670,.T.);
#674=ORIENTED_EDGE('',*,*,#673,.T.);
#675=DIRECTION('',(0.,-1.,0.));
#676=VECTOR('',#675,1.);
#677=CARTESIAN_POINT('',(9.87203077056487,-10.001,13.058004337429));
#678=LINE('',#677,#676);
#679=EDGE_CURVE('E380',#503,#672,#678,.T.);
#680=ORIENTED_EDGE('',*,*,#679,.F.);
#681=EDGE_LOOP('',(#658,#666,#674,#680));
#682=FACE_BOUND('',#681,.T.);
#683=ADVANCED_FACE('F586',(#682),#657,.F.);
#684=CARTESIAN_POINT('',(-10.1412679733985,-0.570466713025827,-18.5695273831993));
#685=DIRECTION('',(0.,-1.,0.));
#686=DIRECTION('',(0.,0.,-1.));
#687=AXIS2_PLACEMENT_3D('',#684,#685,#686);
#688=PLANE('',#687);
#689=ORIENTED_EDGE('',*,*,#673,.F.);
#690=DIRECTION('',(1.,0.,0.));
#691=VECTOR('',#690,1.);
#692=CARTESIAN_POINT('',(25.2903479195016,-0.570466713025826,-13.0580043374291));
#693=LINE('',#692,#691);
#694=CARTESIAN_POINT('',(-10.1412679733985,-0.570466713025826,-13.058004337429));
#695=VERTEX_POINT('',#694);
#696=EDGE_CURVE('E375',#695,#664,#693,.T.);
#697=ORIENTED_EDGE('',*,*,#696,.F.);
#698=DIRECTION('',(0.,0.,1.));
#699=VECTOR('',#698,1.);
#700=CARTESIAN_POINT('',(-10.1412679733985,-0.570466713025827,-18.5695273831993));
#701=LINE('',#700,#699);
#702=CARTESIAN_POINT('',(-10.1412679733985,-0.570466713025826,13.058004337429));
#703=VERTEX_POINT('',#702);
#704=EDGE_CURVE('E459',#695,#703,#701,.T.);
#705=ORIENTED_EDGE('',*,*,#704,.T.);
#706=DIRECTION('',(-1.,0.,0.));
#707=VECTOR('',#706,1.);
#708=CARTESIAN_POINT('',(25.2903479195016,-0.570466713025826,13.058004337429));
#709=LINE('',#708,#707);
#710=EDGE_CURVE('E422',#672,#703,#709,.T.);
#711=ORIENTED_EDGE('',*,*,#710,.F.);
#712=EDGE_LOOP('',(#689,#697,#705,#711));
#713=FACE_BOUND('',#712,.T.);
#714=ADVANCED_FACE('F581',(#713),#688,.F.);
#715=CARTESIAN_POINT('',(-10.1412679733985,5.,-18.5695273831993));
#716=DIRECTION('',(-1.,0.,0.));
#717=DIRECTION('',(0.,0.,1.));
#718=AXIS2_PLACEMENT_3D('',#715,#716,#717);
#719=PLANE('',#718);
#720=ORIENTED_EDGE('',*,*,#704,.F.);
#721=DIRECTION('',(0.,-1.,0.));
#722=VECTOR('',#721,1.);
#723=CARTESIAN_POINT('',(-10.1412679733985,-10.001,-13.058004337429));
#724=LINE('',#723,#722);
#725=EDGE_CURVE('E332',#219,#695,#724,.T.);
#726=ORIENTED_EDGE('',*,*,#725,.F.);
#727=ORIENTED_EDGE('',*,*,#220,.T.);
#728=DIRECTION('',(0.,1.,0.));
#729=VECTOR('',#728,1.);
#730=CARTESIAN_POINT('',(-10.1412679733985,-10.001,13.058004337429));
#731=LINE('',#730,#729);
#732=EDGE_CURVE('E377',#703,#211,#731,.T.);
#733=ORIENTED_EDGE('',*,*,#732,.F.);
#734=EDGE_LOOP('',(#720,#726,#727,#733));
#735=FACE_BOUND('',#734,.T.);
#736=ADVANCED_FACE('F576',(#735),#719,.F.);
#737=CARTESIAN_POINT('',(-7.62838741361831,-10.,-18.5695273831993));
#738=DIRECTION('',(-1.,0.,0.));
#739=DIRECTION('',(0.,0.,1.));
#740=AXIS2_PLACEMENT_3D('',#737,#738,#739);
#741=PLANE('',#740);
#742=ORIENTED_EDGE('',*,*,#459,.F.);
#743=DIRECTION('',(0.,-1.,0.));
#744=VECTOR('',#743,1.);
#745=CARTESIAN_POINT('',(-7.62838741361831,-10.001,-13.058004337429));
#746=LINE('',#745,#744);
#747=CARTESIAN_POINT('',(-7.62838741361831,-6.1347022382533,-13.058004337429));
#748=VERTEX_POINT('',#747);
#749=EDGE_CURVE('E371',#748,#450,#746,.T.);
#750=ORIENTED_EDGE('',*,*,#749,.F.);
#751=DIRECTION('',(0.,0.,1.));
#752=VECTOR('',#751,1.);
#753=CARTESIAN_POINT('',(-7.62838741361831,-6.1347022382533,-18.5695273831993));
#754=LINE('',#753,#752);
#755=CARTESIAN_POINT('',(-7.62838741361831,-6.1347022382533,13.058004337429));
#756=VERTEX_POINT('',#755);
#757=EDGE_CURVE('E449',#748,#756,#754,.T.);
#758=ORIENTED_EDGE('',*,*,#757,.T.);
#759=DIRECTION('',(0.,1.,0.));
#760=VECTOR('',#759,1.);
#761=CARTESIAN_POINT('',(-7.62838741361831,-10.001,13.058004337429));
#762=LINE('',#761,#760);
#763=EDGE_CURVE('E416',#458,#756,#762,.T.);
#764=ORIENTED_EDGE('',*,*,#763,.F.);
#765=EDGE_LOOP('',(#742,#750,#758,#764));
#766=FACE_BOUND('',#765,.T.);
#767=ADVANCED_FACE('F550',(#766),#741,.F.);
#768=CARTESIAN_POINT('',(-7.62838741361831,-6.1347022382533,-18.5695273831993));
#769=DIRECTION('',(0.,1.,0.));
#770=DIRECTION('',(0.,0.,1.));
#771=AXIS2_PLACEMENT_3D('',#768,#769,#770);
#772=PLANE('',#771);
#773=ORIENTED_EDGE('',*,*,#757,.F.);
#774=DIRECTION('',(-1.,0.,0.));
#775=VECTOR('',#774,1.);
#776=CARTESIAN_POINT('',(25.2903479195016,-6.1347022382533,-13.0580043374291));
#777=LINE('',#776,#775);
#778=CARTESIAN_POINT('',(6.01296419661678,-6.1347022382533,-13.058004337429));
#779=VERTEX_POINT('',#778);
#780=EDGE_CURVE('E369',#779,#748,#777,.T.);
#781=ORIENTED_EDGE('',*,*,#780,.F.);
#782=DIRECTION('',(0.,0.,1.));
#783=VECTOR('',#782,1.);
#784=CARTESIAN_POINT('',(6.01296419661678,-6.1347022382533,-18.5695273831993));
#785=LINE('',#784,#783);
#786=CARTESIAN_POINT('',(6.01296419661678,-6.1347022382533,13.058004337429));
#787=VERTEX_POINT('',#786);
#788=EDGE_CURVE('E451',#779,#787,#785,.T.);
#789=ORIENTED_EDGE('',*,*,#788,.T.);
#790=DIRECTION('',(1.,0.,0.));
#791=VECTOR('',#790,1.);
#792=CARTESIAN_POINT('',(25.2903479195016,-6.1347022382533,13.058004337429));
#793=LINE('',#792,#791);
#794=EDGE_CURVE('E413',#756,#787,#793,.T.);
#795=ORIENTED_EDGE('',*,*,#794,.F.);
#796=EDGE_LOOP('',(#773,#781,#789,#795));
#797=FACE_BOUND('',#796,.T.);
#798=ADVANCED_FACE('F546',(#797),#772,.F.);
#799=CARTESIAN_POINT('',(6.01296419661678,-6.1347022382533,-18.5695273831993));
#800=DIRECTION('',(1.,0.,0.));
#801=DIRECTION('',(0.,0.,-1.));
#802=AXIS2_PLACEMENT_3D('',#799,#800,#801);
#803=PLANE('',#802);
#804=ORIENTED_EDGE('',*,*,#788,.F.);
#805=DIRECTION('',(0.,1.,0.));
#806=VECTOR('',#805,1.);
#807=CARTESIAN_POINT('',(6.01296419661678,-10.001,-13.058004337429));
#808=LINE('',#807,#806);
#809=EDGE_CURVE('E367',#581,#779,#808,.T.);
#810=ORIENTED_EDGE('',*,*,#809,.F.);
#811=ORIENTED_EDGE('',*,*,#613,.T.);
#812=DIRECTION('',(0.,-1.,0.));
#813=VECTOR('',#812,1.);
#814=CARTESIAN_POINT('',(6.01296419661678,-10.001,13.058004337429));
#815=LINE('',#814,#813);
#816=EDGE_CURVE('E410',#787,#606,#815,.T.);
#817=ORIENTED_EDGE('',*,*,#816,.F.);
#818=EDGE_LOOP('',(#804,#810,#811,#817));
#819=FACE_BOUND('',#818,.T.);
#820=ADVANCED_FACE('F538',(#819),#803,.F.);
#821=CARTESIAN_POINT('',(-11.3977082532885,-10.001,13.058004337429));
#822=DIRECTION('',(-1.,0.,0.));
#823=DIRECTION('',(0.,0.,1.));
#824=AXIS2_PLACEMENT_3D('',#821,#822,#823);
#825=PLANE('',#824);
#826=ORIENTED_EDGE('',*,*,#473,.T.);
#827=DIRECTION('',(0.,1.,0.));
#828=VECTOR('',#827,1.);
#829=CARTESIAN_POINT('',(-11.3977082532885,-10.001,13.058004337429));
#830=LINE('',#829,#828);
#831=EDGE_CURVE('E404',#466,#203,#830,.T.);
#832=ORIENTED_EDGE('',*,*,#831,.T.);
#833=ORIENTED_EDGE('',*,*,#204,.T.);
#834=ORIENTED_EDGE('',*,*,#72,.F.);
#835=EDGE_LOOP('',(#826,#832,#833,#834));
#836=FACE_BOUND('',#835,.T.);
#837=ADVANCED_FACE('F651',(#836),#825,.F.);
#838=CARTESIAN_POINT('',(25.2903479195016,-10.001,13.058004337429));
#839=DIRECTION('',(0.,0.,-1.));
#840=DIRECTION('',(-1.,0.,0.));
#841=AXIS2_PLACEMENT_3D('',#838,#839,#840);
#842=PLANE('',#841);
#843=ORIENTED_EDGE('',*,*,#679,.T.);
#844=ORIENTED_EDGE('',*,*,#710,.T.);
#845=ORIENTED_EDGE('',*,*,#732,.T.);
#846=ORIENTED_EDGE('',*,*,#212,.T.);
#847=ORIENTED_EDGE('',*,*,#831,.F.);
#848=ORIENTED_EDGE('',*,*,#467,.T.);
#849=ORIENTED_EDGE('',*,*,#763,.T.);
#850=ORIENTED_EDGE('',*,*,#794,.T.);
#851=ORIENTED_EDGE('',*,*,#816,.T.);
#852=ORIENTED_EDGE('',*,*,#607,.T.);
#853=DIRECTION('',(0.,1.,0.));
#854=VECTOR('',#853,1.);
#855=CARTESIAN_POINT('',(25.2903479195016,-10.001,13.058004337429));
#856=LINE('',#855,#854);
#857=EDGE_CURVE('E406',#598,#507,#856,.T.);
#858=ORIENTED_EDGE('',*,*,#857,.T.);
#859=ORIENTED_EDGE('',*,*,#508,.T.);
#860=EDGE_LOOP('',(#843,#844,#845,#846,#847,#848,#849,#850,#851,#852,#858,#859));
#861=FACE_BOUND('',#860,.T.);
#862=ADVANCED_FACE('F533',(#861),#842,.F.);
#863=CARTESIAN_POINT('',(25.2903479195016,-10.001,18.5695273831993));
#864=DIRECTION('',(1.,0.,0.));
#865=DIRECTION('',(0.,0.,-1.));
#866=AXIS2_PLACEMENT_3D('',#863,#864,#865);
#867=PLANE('',#866);
#868=ORIENTED_EDGE('',*,*,#599,.T.);
#869=ORIENTED_EDGE('',*,*,#532,.T.);
#870=ORIENTED_EDGE('',*,*,#516,.T.);
#871=ORIENTED_EDGE('',*,*,#857,.F.);
#872=EDGE_LOOP('',(#868,#869,#870,#871));
#873=FACE_BOUND('',#872,.T.);
#874=ADVANCED_FACE('F531',(#873),#867,.F.);
#875=CARTESIAN_POINT('',(25.2903479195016,-10.001,-18.5695273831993));
#876=DIRECTION('',(1.,0.,0.));
#877=DIRECTION('',(0.,0.,-1.));
#878=AXIS2_PLACEMENT_3D('',#875,#876,#877);
#879=PLANE('',#878);
#880=ORIENTED_EDGE('',*,*,#588,.T.);
#881=DIRECTION('',(0.,1.,0.));
#882=VECTOR('',#881,1.);
#883=CARTESIAN_POINT('',(25.2903479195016,-10.001,-13.0580043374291));
#884=LINE('',#883,#882);
#885=EDGE_CURVE('E361',#579,#491,#884,.T.);
#886=ORIENTED_EDGE('',*,*,#885,.T.);
#887=ORIENTED_EDGE('',*,*,#492,.T.);
#888=ORIENTED_EDGE('',*,*,#424,.F.);
#889=EDGE_LOOP('',(#880,#886,#887,#888));
#890=FACE_BOUND('',#889,.T.);
#891=ADVANCED_FACE('F516',(#890),#879,.F.);
#892=CARTESIAN_POINT('',(25.2903479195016,-10.001,-13.0580043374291));
#893=DIRECTION('',(0.,0.,1.));
#894=DIRECTION('',(1.,0.,0.));
#895=AXIS2_PLACEMENT_3D('',#892,#893,#894);
#896=PLANE('',#895);
#897=ORIENTED_EDGE('',*,*,#665,.T.);
#898=ORIENTED_EDGE('',*,*,#496,.T.);
#899=ORIENTED_EDGE('',*,*,#885,.F.);
#900=ORIENTED_EDGE('',*,*,#582,.T.);
#901=ORIENTED_EDGE('',*,*,#809,.T.);
#902=ORIENTED_EDGE('',*,*,#780,.T.);
#903=ORIENTED_EDGE('',*,*,#749,.T.);
#904=ORIENTED_EDGE('',*,*,#451,.T.);
#905=DIRECTION('',(0.,1.,0.));
#906=VECTOR('',#905,1.);
#907=CARTESIAN_POINT('',(-11.3977082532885,-10.001,-13.058004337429));
#908=LINE('',#907,#906);
#909=EDGE_CURVE('E363',#442,#227,#908,.T.);
#910=ORIENTED_EDGE('',*,*,#909,.T.);
#911=ORIENTED_EDGE('',*,*,#228,.T.);
#912=ORIENTED_EDGE('',*,*,#725,.T.);
#913=ORIENTED_EDGE('',*,*,#696,.T.);
#914=EDGE_LOOP('',(#897,#898,#899,#900,#901,#902,#903,#904,#910,#911,#912,#913));
#915=FACE_BOUND('',#914,.T.);
#916=ADVANCED_FACE('F542',(#915),#896,.F.);
#917=CARTESIAN_POINT('',(-11.3977082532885,-10.001,-13.058004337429));
#918=DIRECTION('',(-1.,0.,0.));
#919=DIRECTION('',(0.,0.,1.));
#920=AXIS2_PLACEMENT_3D('',#917,#918,#919);
#921=PLANE('',#920);
#922=ORIENTED_EDGE('',*,*,#443,.T.);
#923=ORIENTED_EDGE('',*,*,#157,.T.);
#924=ORIENTED_EDGE('',*,*,#234,.T.);
#925=ORIENTED_EDGE('',*,*,#909,.F.);
#926=EDGE_LOOP('',(#922,#923,#924,#925));
#927=FACE_BOUND('',#926,.T.);
#928=ADVANCED_FACE('F564',(#927),#921,.F.);
#929=CARTESIAN_POINT('',(75.7086650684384,-2.5,0.));
#930=DIRECTION('',(-1.,0.,0.));
#931=DIRECTION('',(0.,0.,1.));
#932=AXIS2_PLACEMENT_3D('',#929,#930,#931);
#933=CYLINDRICAL_SURFACE('',#932,5.);
#934=CARTESIAN_POINT('',(73.7086650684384,-2.5,0.));
#935=DIRECTION('',(1.,0.,0.));
#936=DIRECTION('',(0.,0.,-1.));
#937=AXIS2_PLACEMENT_3D('',#934,#935,#936);
#938=CIRCLE('',#937,5.);
#939=CARTESIAN_POINT('',(73.7086650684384,-2.5,-4.99999999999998));
#940=VERTEX_POINT('',#939);
#941=EDGE_CURVE('E39',#940,#940,#938,.F.);
#942=ORIENTED_EDGE('',*,*,#941,.T.);
#943=EDGE_LOOP('',(#942));
#944=FACE_BOUND('',#943,.T.);
#945=ORIENTED_EDGE('',*,*,#409,.T.);
#946=EDGE_LOOP('',(#945));
#947=FACE_BOUND('',#946,.T.);
#948=ADVANCED_FACE('F278',(#944,#947),#933,.T.);
#949=CARTESIAN_POINT('',(75.7086650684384,-2.5,0.));
#950=DIRECTION('',(1.,0.,0.));
#951=DIRECTION('',(0.,0.,-1.));
#952=AXIS2_PLACEMENT_3D('',#949,#950,#951);
#953=PLANE('',#952);
#954=CARTESIAN_POINT('',(75.7086650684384,-2.5,0.));
#955=DIRECTION('',(1.,0.,0.));
#956=DIRECTION('',(0.,0.,-1.));
#957=AXIS2_PLACEMENT_3D('',#954,#955,#956);
#958=CIRCLE('',#957,3.);
#959=CARTESIAN_POINT('',(75.7086650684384,-2.5,-2.99999999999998));
#960=VERTEX_POINT('',#959);
#961=EDGE_CURVE('E267',#960,#960,#958,.T.);
#962=ORIENTED_EDGE('',*,*,#961,.T.);
#963=EDGE_LOOP('',(#962));
#964=FACE_BOUND('',#963,.T.);
#965=CARTESIAN_POINT('',(75.7086650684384,-2.5,0.));
#966=DIRECTION('',(1.,0.,0.));
#967=DIRECTION('',(0.,0.,-1.));
#968=AXIS2_PLACEMENT_3D('',#965,#966,#967);
#969=CIRCLE('',#968,2.);
#970=CARTESIAN_POINT('',(75.7086650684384,-2.5,-1.99999999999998));
#971=VERTEX_POINT('',#970);
#972=EDGE_CURVE('E296',#971,#971,#969,.T.);
#973=ORIENTED_EDGE('',*,*,#972,.F.);
#974=EDGE_LOOP('',(#973));
#975=FACE_BOUND('',#974,.T.);
#976=ADVANCED_FACE('F289',(#964,#975),#953,.T.);
#977=CARTESIAN_POINT('',(37.7086650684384,0.,5.00000000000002));
#978=DIRECTION('',(1.,0.,0.));
#979=DIRECTION('',(0.,0.,-1.));
#980=AXIS2_PLACEMENT_3D('',#977,#978,#979);
#981=PLANE('',#980);
#982=CARTESIAN_POINT('',(37.7086650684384,-2.5,0.));
#983=DIRECTION('',(1.,0.,0.));
#984=DIRECTION('',(0.,0.,-1.));
#985=AXIS2_PLACEMENT_3D('',#982,#983,#984);
#986=CIRCLE('',#985,2.);
#987=CARTESIAN_POINT('',(37.7086650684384,-2.5,-1.99999999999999));
#988=VERTEX_POINT('',#987);
#989=EDGE_CURVE('E298',#988,#988,#986,.F.);
#990=ORIENTED_EDGE('',*,*,#989,.F.);
#991=EDGE_LOOP('',(#990));
#992=FACE_BOUND('',#991,.T.);
#993=ORIENTED_EDGE('',*,*,#556,.T.);
#994=DIRECTION('',(0.,-1.,0.));
#995=VECTOR('',#994,1.);
#996=CARTESIAN_POINT('',(37.7086650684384,0.,5.00000000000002));
#997=LINE('',#996,#995);
#998=CARTESIAN_POINT('',(37.7086650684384,0.,5.00000000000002));
#999=VERTEX_POINT('',#998);
#1000=EDGE_CURVE('E329',#999,#545,#997,.T.);
#1001=ORIENTED_EDGE('',*,*,#1000,.F.);
#1002=DIRECTION('',(0.,0.,1.));
#1003=VECTOR('',#1002,1.);
#1004=CARTESIAN_POINT('',(37.7086650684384,0.,5.00000000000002));
#1005=LINE('',#1004,#1003);
#1006=CARTESIAN_POINT('',(37.7086650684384,0.,-4.99999999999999));
#1007=VERTEX_POINT('',#1006);
#1008=EDGE_CURVE('E317',#1007,#999,#1005,.T.);
#1009=ORIENTED_EDGE('',*,*,#1008,.F.);
#1010=DIRECTION('',(0.,-1.,0.));
#1011=VECTOR('',#1010,1.);
#1012=CARTESIAN_POINT('',(37.7086650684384,0.,-4.99999999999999));
#1013=LINE('',#1012,#1011);
#1014=EDGE_CURVE('E330',#1007,#555,#1013,.T.);
#1015=ORIENTED_EDGE('',*,*,#1014,.T.);
#1016=EDGE_LOOP('',(#993,#1001,#1009,#1015));
#1017=FACE_BOUND('',#1016,.T.);
#1018=ADVANCED_FACE('F292',(#992,#1017),#981,.F.);
#1019=CARTESIAN_POINT('',(37.7086650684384,0.,-4.99999999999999));
#1020=DIRECTION('',(0.,0.,-1.));
#1021=DIRECTION('',(-1.,0.,0.));
#1022=AXIS2_PLACEMENT_3D('',#1019,#1020,#1021);
#1023=PLANE('',#1022);
#1024=ORIENTED_EDGE('',*,*,#564,.T.);
#1025=ORIENTED_EDGE('',*,*,#1014,.F.);
#1026=DIRECTION('',(1.,0.,0.));
#1027=VECTOR('',#1026,1.);
#1028=CARTESIAN_POINT('',(37.7086650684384,0.,-4.99999999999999));
#1029=LINE('',#1028,#1027);
#1030=CARTESIAN_POINT('',(28.7663146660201,0.,-4.99999999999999));
#1031=VERTEX_POINT('',#1030);
#1032=EDGE_CURVE('E326',#1031,#1007,#1029,.T.);
#1033=ORIENTED_EDGE('',*,*,#1032,.F.);
#1034=DIRECTION('',(0.,-1.,0.));
#1035=VECTOR('',#1034,1.);
#1036=CARTESIAN_POINT('',(28.7663146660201,0.,-4.99999999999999));
#1037=LINE('',#1036,#1035);
#1038=EDGE_CURVE('E333',#1031,#563,#1037,.T.);
#1039=ORIENTED_EDGE('',*,*,#1038,.T.);
#1040=EDGE_LOOP('',(#1024,#1025,#1033,#1039));
#1041=FACE_BOUND('',#1040,.T.);
#1042=ADVANCED_FACE('F709',(#1041),#1023,.F.);
#1043=CARTESIAN_POINT('',(28.7663146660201,0.,5.00000000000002));
#1044=DIRECTION('',(-1.,0.,0.));
#1045=DIRECTION('',(0.,0.,1.));
#1046=AXIS2_PLACEMENT_3D('',#1043,#1044,#1045);
#1047=PLANE('',#1046);
#1048=ORIENTED_EDGE('',*,*,#570,.T.);
#1049=ORIENTED_EDGE('',*,*,#1038,.F.);
#1050=DIRECTION('',(0.,0.,-1.));
#1051=VECTOR('',#1050,1.);
#1052=CARTESIAN_POINT('',(28.7663146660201,0.,5.00000000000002));
#1053=LINE('',#1052,#1051);
#1054=CARTESIAN_POINT('',(28.7663146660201,0.,5.00000000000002));
#1055=VERTEX_POINT('',#1054);
#1056=EDGE_CURVE('E323',#1055,#1031,#1053,.T.);
#1057=ORIENTED_EDGE('',*,*,#1056,.F.);
#1058=DIRECTION('',(0.,-1.,0.));
#1059=VECTOR('',#1058,1.);
#1060=CARTESIAN_POINT('',(28.7663146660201,0.,5.00000000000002));
#1061=LINE('',#1060,#1059);
#1062=EDGE_CURVE('E335',#1055,#547,#1061,.T.);
#1063=ORIENTED_EDGE('',*,*,#1062,.T.);
#1064=EDGE_LOOP('',(#1048,#1049,#1057,#1063));
#1065=FACE_BOUND('',#1064,.T.);
#1066=ADVANCED_FACE('F712',(#1065),#1047,.F.);
#1067=CARTESIAN_POINT('',(37.7086650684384,0.,5.00000000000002));
#1068=DIRECTION('',(0.,0.,1.));
#1069=DIRECTION('',(1.,0.,0.));
#1070=AXIS2_PLACEMENT_3D('',#1067,#1068,#1069);
#1071=PLANE('',#1070);
#1072=ORIENTED_EDGE('',*,*,#548,.T.);
#1073=ORIENTED_EDGE('',*,*,#1062,.F.);
#1074=DIRECTION('',(-1.,0.,0.));
#1075=VECTOR('',#1074,1.);
#1076=CARTESIAN_POINT('',(37.7086650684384,0.,5.00000000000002));
#1077=LINE('',#1076,#1075);
#1078=EDGE_CURVE('E320',#999,#1055,#1077,.T.);
#1079=ORIENTED_EDGE('',*,*,#1078,.F.);
#1080=ORIENTED_EDGE('',*,*,#1000,.T.);
#1081=EDGE_LOOP('',(#1072,#1073,#1079,#1080));
#1082=FACE_BOUND('',#1081,.T.);
#1083=ADVANCED_FACE('F707',(#1082),#1071,.F.);
#1084=CARTESIAN_POINT('',(37.7086650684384,0.,5.00000000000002));
#1085=DIRECTION('',(0.,1.,0.));
#1086=DIRECTION('',(0.,0.,1.));
#1087=AXIS2_PLACEMENT_3D('',#1084,#1085,#1086);
#1088=PLANE('',#1087);
#1089=ORIENTED_EDGE('',*,*,#1008,.T.);
#1090=ORIENTED_EDGE('',*,*,#1078,.T.);
#1091=ORIENTED_EDGE('',*,*,#1056,.T.);
#1092=ORIENTED_EDGE('',*,*,#1032,.T.);
#1093=EDGE_LOOP('',(#1089,#1090,#1091,#1092));
#1094=FACE_BOUND('',#1093,.T.);
#1095=ADVANCED_FACE('F704',(#1094),#1088,.F.);
#1096=CARTESIAN_POINT('',(-40.7096650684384,-2.5,0.));
#1097=DIRECTION('',(1.,0.,0.));
#1098=DIRECTION('',(0.,0.,-1.));
#1099=AXIS2_PLACEMENT_3D('',#1096,#1097,#1098);
#1100=CYLINDRICAL_SURFACE('',#1099,2.);
#1101=CARTESIAN_POINT('',(75.7086650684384,-2.5,-1.99999999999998));
#1102=CARTESIAN_POINT('',(75.3128317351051,-2.5,-1.99999999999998));
#1103=CARTESIAN_POINT('',(74.9169984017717,-2.5,-1.99999999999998));
#1104=CARTESIAN_POINT('',(74.1253317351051,-2.5,-1.99999999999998));
#1105=CARTESIAN_POINT('',(73.7294984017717,-2.5,-1.99999999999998));
#1106=CARTESIAN_POINT('',(72.9378317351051,-2.5,-1.99999999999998));
#1107=CARTESIAN_POINT('',(72.5419984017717,-2.5,-1.99999999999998));
#1108=CARTESIAN_POINT('',(71.7503317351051,-2.5,-1.99999999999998));
#1109=CARTESIAN_POINT('',(71.3544984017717,-2.5,-1.99999999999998));
#1110=CARTESIAN_POINT('',(70.5628317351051,-2.5,-1.99999999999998));
#1111=CARTESIAN_POINT('',(70.1669984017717,-2.5,-1.99999999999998));
#1112=CARTESIAN_POINT('',(69.3753317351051,-2.5,-1.99999999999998));
#1113=CARTESIAN_POINT('',(68.9794984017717,-2.5,-1.99999999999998));
#1114=CARTESIAN_POINT('',(68.1878317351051,-2.5,-1.99999999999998));
#1115=CARTESIAN_POINT('',(67.7919984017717,-2.5,-1.99999999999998));
#1116=CARTESIAN_POINT('',(67.0003317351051,-2.5,-1.99999999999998));
#1117=CARTESIAN_POINT('',(66.6044984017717,-2.5,-1.99999999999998));
#1118=CARTESIAN_POINT('',(65.8128317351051,-2.5,-1.99999999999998));
#1119=CARTESIAN_POINT('',(65.4169984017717,-2.5,-1.99999999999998));
#1120=CARTESIAN_POINT('',(64.6253317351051,-2.5,-1.99999999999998));
#1121=CARTESIAN_POINT('',(64.2294984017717,-2.5,-1.99999999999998));
#1122=CARTESIAN_POINT('',(63.4378317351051,-2.5,-1.99999999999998));
#1123=CARTESIAN_POINT('',(63.0419984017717,-2.5,-1.99999999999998));
#1124=CARTESIAN_POINT('',(62.2503317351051,-2.5,-1.99999999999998));
#1125=CARTESIAN_POINT('',(61.8544984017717,-2.5,-1.99999999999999));
#1126=CARTESIAN_POINT('',(61.0628317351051,-2.5,-1.99999999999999));
#1127=CARTESIAN_POINT('',(60.6669984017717,-2.5,-1.99999999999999));
#1128=CARTESIAN_POINT('',(59.8753317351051,-2.5,-1.99999999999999));
#1129=CARTESIAN_POINT('',(59.4794984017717,-2.5,-1.99999999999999));
#1130=CARTESIAN_POINT('',(58.6878317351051,-2.5,-1.99999999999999));
#1131=CARTESIAN_POINT('',(58.2919984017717,-2.5,-1.99999999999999));
#1132=CARTESIAN_POINT('',(57.5003317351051,-2.5,-1.99999999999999));
#1133=CARTESIAN_POINT('',(57.1044984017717,-2.5,-1.99999999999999));
#1134=CARTESIAN_POINT('',(56.3128317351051,-2.5,-1.99999999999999));
#1135=CARTESIAN_POINT('',(55.9169984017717,-2.5,-1.99999999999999));
#1136=CARTESIAN_POINT('',(55.1253317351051,-2.5,-1.99999999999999));
#1137=CARTESIAN_POINT('',(54.7294984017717,-2.5,-1.99999999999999));
#1138=CARTESIAN_POINT('',(53.9378317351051,-2.5,-1.99999999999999));
#1139=CARTESIAN_POINT('',(53.5419984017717,-2.5,-1.99999999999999));
#1140=CARTESIAN_POINT('',(52.7503317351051,-2.5,-1.99999999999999));
#1141=CARTESIAN_POINT('',(52.3544984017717,-2.5,-1.99999999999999));
#1142=CARTESIAN_POINT('',(51.5628317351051,-2.5,-1.99999999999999));
#1143=CARTESIAN_POINT('',(51.1669984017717,-2.5,-1.99999999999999));
#1144=CARTESIAN_POINT('',(50.3753317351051,-2.5,-1.99999999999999));
#1145=CARTESIAN_POINT('',(49.9794984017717,-2.5,-1.99999999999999));
#1146=CARTESIAN_POINT('',(49.1878317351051,-2.5,-1.99999999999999));
#1147=CARTESIAN_POINT('',(48.7919984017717,-2.5,-1.99999999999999));
#1148=CARTESIAN_POINT('',(48.0003317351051,-2.5,-1.99999999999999));
#1149=CARTESIAN_POINT('',(47.6044984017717,-2.5,-1.99999999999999));
#1150=CARTESIAN_POINT('',(46.812831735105,-2.5,-1.99999999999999));
#1151=CARTESIAN_POINT('',(46.4169984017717,-2.5,-1.99999999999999));
#1152=CARTESIAN_POINT('',(45.625331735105,-2.5,-1.99999999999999));
#1153=CARTESIAN_POINT('',(45.2294984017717,-2.5,-1.99999999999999));
#1154=CARTESIAN_POINT('',(44.4378317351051,-2.5,-1.99999999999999));
#1155=CARTESIAN_POINT('',(44.0419984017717,-2.5,-1.99999999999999));
#1156=CARTESIAN_POINT('',(43.2503317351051,-2.5,-1.99999999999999));
#1157=CARTESIAN_POINT('',(42.8544984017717,-2.5,-1.99999999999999));
#1158=CARTESIAN_POINT('',(42.062831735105,-2.5,-1.99999999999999));
#1159=CARTESIAN_POINT('',(41.6669984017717,-2.5,-1.99999999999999));
#1160=CARTESIAN_POINT('',(40.875331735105,-2.5,-1.99999999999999));
#1161=CARTESIAN_POINT('',(40.4794984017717,-2.5,-1.99999999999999));
#1162=CARTESIAN_POINT('',(39.687831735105,-2.5,-1.99999999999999));
#1163=CARTESIAN_POINT('',(39.2919984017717,-2.5,-1.99999999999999));
#1164=CARTESIAN_POINT('',(38.500331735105,-2.5,-1.99999999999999));
#1165=CARTESIAN_POINT('',(38.1044984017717,-2.5,-1.99999999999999));
#1166=CARTESIAN_POINT('',(37.7086650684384,-2.5,-1.99999999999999));
#1167=B_SPLINE_CURVE_WITH_KNOTS('',3,(#1101,#1102,#1103,#1104,#1105,#1106,#1107,#1108,#1109,
#1110,#1111,#1112,#1113,#1114,#1115,#1116,#1117,#1118,#1119,#1120,#1121,#1122,#1123,#1124,#1125,
#1126,#1127,#1128,#1129,#1130,#1131,#1132,#1133,#1134,#1135,#1136,#1137,#1138,#1139,#1140,#1141,
#1142,#1143,#1144,#1145,#1146,#1147,#1148,#1149,#1150,#1151,#1152,#1153,#1154,#1155,#1156,#1157,
#1158,#1159,#1160,#1161,#1162,#1163,#1164,#1165,#1166),.UNSPECIFIED.,.F.,.F.,(4,2,2,2,2,2,2,2,2,
2,2,2,2,2,2,2,2,2,2,2,2,2,2,2,2,2,2,2,2,2,2,2,4),(0.,1.18750000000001,2.375,3.5625,4.75,
5.93750000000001,7.12500000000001,8.3125,9.50000000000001,10.6875,11.875,13.0625,14.25,15.4375,
16.625,17.8125,19.,20.1875,21.375,22.5625,23.75,24.9375,26.125,27.3125,28.5,29.6875,30.875,
32.0625,33.25,34.4375,35.625,36.8125,38.),.UNSPECIFIED.);
#1168=EDGE_CURVE('BSEAM285',#971,#988,#1167,.T.);
#1169=ORIENTED_EDGE('',*,*,#972,.T.);
#1170=ORIENTED_EDGE('',*,*,#989,.T.);
#1171=ORIENTED_EDGE('',*,*,#1168,.T.);
#1172=ORIENTED_EDGE('',*,*,#1168,.F.);
#1173=EDGE_LOOP('',(#1169,#1171,#1170,#1172));
#1174=FACE_BOUND('',#1173,.T.);
#1175=ADVANCED_FACE('F285',(#1174),#1100,.F.);
#1176=CARTESIAN_POINT('',(73.7086650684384,-2.5,0.));
#1177=DIRECTION('',(1.,0.,0.));
#1178=DIRECTION('',(0.,0.,-1.));
#1179=AXIS2_PLACEMENT_3D('',#1176,#1177,#1178);
#1180=TOROIDAL_SURFACE('',#1179,3.,2.);
#1181=ORIENTED_EDGE('',*,*,#941,.F.);
#1182=EDGE_LOOP('',(#1181));
#1183=FACE_BOUND('',#1182,.T.);
#1184=ORIENTED_EDGE('',*,*,#961,.F.);
#1185=EDGE_LOOP('',(#1184));
#1186=FACE_BOUND('',#1185,.T.);
#1187=ADVANCED_FACE('F281',(#1183,#1186),#1180,.T.);
#1188=CARTESIAN_POINT('',(-22.0774506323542,3.7238100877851,18.5695273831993));
#1189=DIRECTION('',(-1.,0.,0.));
#1190=DIRECTION('',(0.,-1.,0.));
#1191=AXIS2_PLACEMENT_3D('',#1188,#1189,#1190);
#1192=PLANE('',#1191);
#1193=ORIENTED_EDGE('',*,*,#195,.T.);
#1194=ORIENTED_EDGE('',*,*,#141,.T.);
#1195=DIRECTION('',(0.,0.,-1.));
#1196=VECTOR('',#1195,1.);
#1197=CARTESIAN_POINT('',(-22.0774506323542,3.7238100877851,18.5695273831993));
#1198=LINE('',#1197,#1196);
#1199=EDGE_CURVE('E918',#31,#132,#1198,.T.);
#1200=ORIENTED_EDGE('',*,*,#1199,.F.);
#1201=ORIENTED_EDGE('',*,*,#86,.T.);
#1202=EDGE_LOOP('',(#1193,#1194,#1200,#1201));
#1203=FACE_BOUND('',#1202,.T.);
#1204=ADVANCED_FACE('F284',(#1203),#1192,.T.);
#1205=CARTESIAN_POINT('',(-40.7086650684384,3.7238100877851,18.5695273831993));
#1206=DIRECTION('',(0.,1.,0.));
#1207=DIRECTION('',(0.,0.,1.));
#1208=AXIS2_PLACEMENT_3D('',#1205,#1206,#1207);
#1209=PLANE('',#1208);
#1210=ORIENTED_EDGE('',*,*,#350,.T.);
#1211=ORIENTED_EDGE('',*,*,#252,.T.);
#1212=ORIENTED_EDGE('',*,*,#290,.T.);
#1213=ORIENTED_EDGE('',*,*,#321,.T.);
#1214=EDGE_LOOP('',(#1210,#1211,#1212,#1213));
#1215=FACE_BOUND('',#1214,.T.);
#1216=ORIENTED_EDGE('',*,*,#1199,.T.);
#1217=ORIENTED_EDGE('',*,*,#133,.T.);
#1218=ORIENTED_EDGE('',*,*,#102,.F.);
#1219=ORIENTED_EDGE('',*,*,#32,.T.);
#1220=EDGE_LOOP('',(#1216,#1217,#1218,#1219));
#1221=FACE_BOUND('',#1220,.T.);
#1222=ADVANCED_FACE('F244',(#1215,#1221),#1209,.T.);
#1223=CLOSED_SHELL('',(#90,#121,#184,#238,#278,#309,#340,#362,#413,#431,#485,#524,#539,#617,
#640,#652,#683,#714,#736,#767,#798,#820,#837,#862,#874,#891,#916,#928,#948,#976,#1018,#1042,
#1066,#1083,#1095,#1175,#1187,#1204,#1222));
#1224=MANIFOLD_SOLID_BREP('B2',#1223);
#1225=ADVANCED_BREP_SHAPE_REPRESENTATION('',(#18,#1224),#14);
#1226=SHAPE_DEFINITION_REPRESENTATION(#9,#1225);
ENDSEC;
END-ISO-10303-21;
